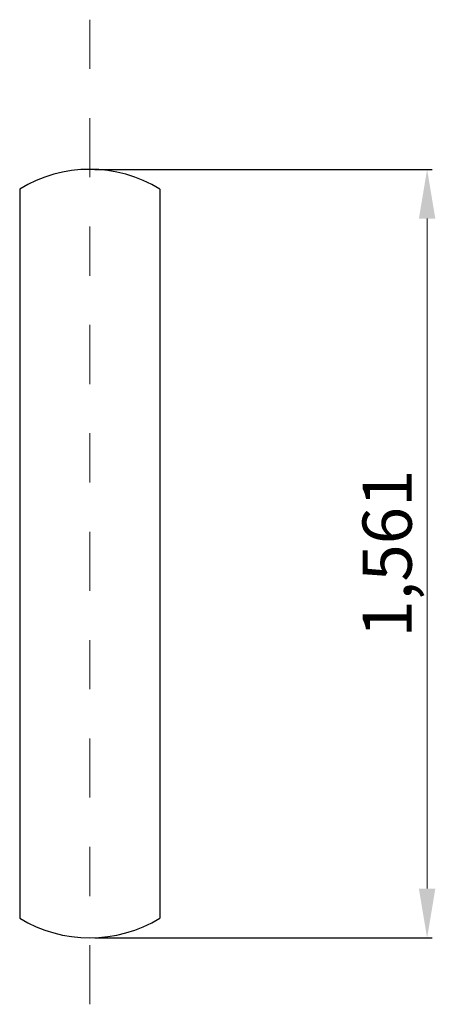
# Model space of a CAD drawing. Units: inches. Extents: x 1.86 to 2.7, y -0.2 to 1.8.
import ezdxf

# ---------------------------------------------------------------- set-up
doc = ezdxf.new("R2010")
doc.units = ezdxf.units.IN
doc.header["$LTSCALE"] = 0.01
doc.linetypes.add('ACAD_ISO10W100', pattern=[18, 12, -3, 0, -3])
doc.dimstyles.new('ISO-25', dxfattribs={"dimtxt": 0.1, "dimasz": 0.1, "dimexe": 0.01, "dimexo": 0.01, "dimgap": 0.01, "dimtad": 1, "dimdec": 3, "dimtxsty": 'Standard', "dimcen": 0.1, "dimadec": 0, "dimazin": 0, "dimtfac": 1, "dimtdec": 3, "dimtmove": 0, "dimatfit": 3, "dimfxl": 0, "dimlwd": 13, "dimarcsym": 0})

# ---------------------------------------------------------------- blocks, each defined once
blk = doc.blocks.new('*D2')
at = {"color": 0, "lineweight": -2, "ltscale": 0.13}
for p, q in [((2.01, 1.496), (2.6954, 1.496)), ((2.01, -0.065), (2.6954, -0.065))]:
    blk.add_line(p, q, dxfattribs=at)
at = {"color": 0, "lineweight": 13, "ltscale": 0.13}
blk.add_line((2.6854, 0.035), (2.6854, 1.396), dxfattribs=at)
for points in [[(2.6687, 1.396), (2.7021, 1.396), (2.6854, 1.496)], [(2.6687, 0.035), (2.7021, 0.035), (2.6854, -0.065)]]:
    blk.add_solid(points, dxfattribs=at)
at = {"layer": 'Defpoints', "color": 0, "lineweight": 13, "ltscale": 0.13}
for p in [(2, 1.496), (2.6854, 1.496), (2, -0.065)]:
    blk.add_point(p, dxfattribs=at)
at = {"color": 0, "lineweight": 13, "ltscale": 0.13, "insert": (2.6171, 0.7155), "char_height": 0.1, "attachment_point": 5, "rotation": 90}
blk.add_mtext('1,561', dxfattribs=at)

msp = doc.modelspace()

# ---------------------------------------------------------------- linework, layer by layer
at = {"color": 1, "linetype": 'ACAD_ISO10W100', "lineweight": 13}
msp.add_line((2, -0.2), (2, 1.8), dxfattribs=at)
at = {"lineweight": 25, "ltscale": 0.13}
for p, q in [((1.8575, 1.456), (1.8575, -0.025)), ((2.1425, 1.456), (2.1425, -0.025))]:
    msp.add_line(p, q, dxfattribs=at)
for centre, start, end in [((2, 1.2222), 58.641, 121.359), ((2, 0.2088), 238.641, 301.359)]:
    msp.add_arc(centre, 0.2738, start, end, dxfattribs=at)

# ---------------------------------------------------------------- dimensions: what is measured, and where the dimension line sits
at = {"color": 3, "lineweight": 13, "ltscale": 0.13}
dim = msp.add_linear_dim(base=(2.6854, 1.496), p1=(2, -0.065), p2=(2, 1.496), angle=90, dimstyle='ISO-25', dxfattribs=at)
dim.commit()
dim.dimension.update_dxf_attribs({"geometry": '*D2', "text_midpoint": (2.6171, 0.7155)})

doc.saveas('drawing.dxf')
